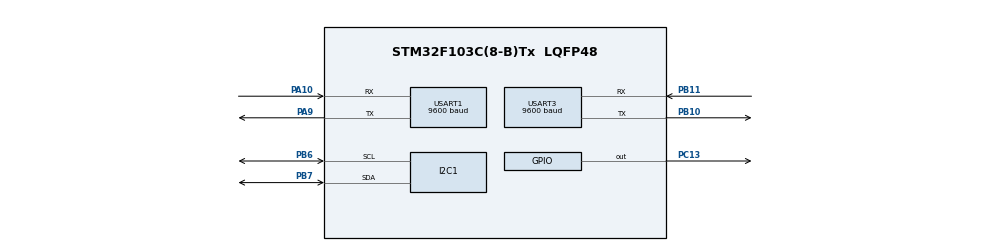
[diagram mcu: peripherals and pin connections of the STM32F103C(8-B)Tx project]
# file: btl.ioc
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Mcu.Family=STM32F1
Mcu.Name=STM32F103C(8-B)Tx
Mcu.Package=LQFP48
NVIC.PriorityGroup=NVIC_PRIORITYGROUP_4
PA10.Mode=Asynchronous
PA10.Signal=USART1_RX
PA13.Mode=Serial_Wire
PA13.Signal=SYS_JTMS-SWDIO
PA14.Mode=Serial_Wire
PA14.Signal=SYS_JTCK-SWCLK
PA9.Mode=Asynchronous
PA9.Signal=USART1_TX
PB10.Mode=Asynchronous
PB10.Signal=USART3_TX
PB11.Mode=Asynchronous
PB11.Signal=USART3_RX
PB6.Mode=I2C
PB6.Signal=I2C1_SCL
PB7.Mode=I2C
PB7.Signal=I2C1_SDA
PC13-TAMPER-RTC.Signal=GPIO_Output
ProjectManager.HeapSize=0x200
ProjectManager.StackSize=0x400
ProjectManager.TargetToolchain=MDK-ARM V5.32
RCC.APB1Freq_Value=8000000
RCC.APB2Freq_Value=8000000
USART1.BaudRate=9600
USART1.VirtualMode=VM_ASYNC
USART3.BaudRate=9600
USART3.VirtualMode=VM_ASYNC
board=custom

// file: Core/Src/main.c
/* USER CODE BEGIN Header */
/**
  ******************************************************************************
  * @file           : main.c
  * @brief          : Main program body
  ******************************************************************************
  * @attention
  *
  * Copyright (c) 2022 STMicroelectronics.
  * All rights reserved.
  *
  * This software is licensed under terms that can be found in the LICENSE file
  * in the root directory of this software component.
  * If no LICENSE file comes with this software, it is provided AS-IS.
  *
  ******************************************************************************
  */
/* USER CODE END Header */
#include "main.h"
#include "string.h"

/* USER CODE BEGIN PTD */
#define SLAVE_ADDRESS_LCD 0x4E
/* USER CODE END PTD */

I2C_HandleTypeDef hi2c1;

UART_HandleTypeDef huart1;
UART_HandleTypeDef huart3;

uint8_t data[20];
uint8_t length;
uint8_t read_buffer;

void SystemClock_Config(void);
static void MX_GPIO_Init(void);
static void MX_I2C1_Init(void);
static void MX_USART1_UART_Init(void);
static void MX_USART3_UART_Init(void);

void lcd_init (void);

void lcd_send_cmd (char cmd);

void lcd_send_data (char data);

void lcd_send_string (char *str, int length);

void lcd_put_cur(int row, int col);

void lcd_clear (void);

int main(void)
{
  /* USER CODE BEGIN 1 */
	int i;
  /* USER CODE END 1 */

  /* MCU Configuration--------------------------------------------------------*/

  /* Reset of all peripherals, Initializes the Flash interface and the Systick. */
  HAL_Init();

  /* Configure the system clock */
  SystemClock_Config();

  /* Initialize all configured peripherals */
  MX_GPIO_Init();
  MX_I2C1_Init();
  MX_USART1_UART_Init();
  MX_USART3_UART_Init();
  /* USER CODE BEGIN 2 */
	lcd_init();
  /* Infinite loop */
  while (1)
  {
		HAL_StatusTypeDef status = HAL_UART_Receive(&huart1, &read_buffer, 1, 1000);
		if (status == HAL_TIMEOUT) {
			continue;
		}

		HAL_UART_Transmit(&huart1, &read_buffer, 1, 1000);

		data[length] = read_buffer;
		if (read_buffer == 13) {
			HAL_GPIO_TogglePin(GPIOC, GPIO_PIN_13);
			HAL_UART_Transmit(&huart3, data, length, 1000);
			HAL_UART_Transmit(&huart3, (uint8_t *)"\r\n", 2, 1000);
			HAL_UART_Transmit(&huart1, (uint8_t *)"\r\n", 2, 1000);

			lcd_clear();
			lcd_put_cur(0, 0);
			lcd_send_string((char *)data, length);

			length = 0;
		} else {
			length++;
		}

		HAL_GPIO_TogglePin(GPIOC, GPIO_PIN_13);
  }
}

void SystemClock_Config(void)
{
  RCC_OscInitTypeDef RCC_OscInitStruct = {0};
  RCC_ClkInitTypeDef RCC_ClkInitStruct = {0};

  /** Initializes the RCC Oscillators according to the specified parameters
  * in the RCC_OscInitTypeDef structure.
  */
  RCC_OscInitStruct.OscillatorType = RCC_OSCILLATORTYPE_HSI;
  RCC_OscInitStruct.HSIState = RCC_HSI_ON;
  RCC_OscInitStruct.HSICalibrationValue = RCC_HSICALIBRATION_DEFAULT;
  RCC_OscInitStruct.PLL.PLLState = RCC_PLL_NONE;
  if (HAL_RCC_OscConfig(&RCC_OscInitStruct) != HAL_OK)
  {
    Error_Handler();
  }

  /** Initializes the CPU, AHB and APB buses clocks
  */
  RCC_ClkInitStruct.ClockType = RCC_CLOCKTYPE_HCLK|RCC_CLOCKTYPE_SYSCLK
                              |RCC_CLOCKTYPE_PCLK1|RCC_CLOCKTYPE_PCLK2;
  RCC_ClkInitStruct.SYSCLKSource = RCC_SYSCLKSOURCE_HSI;
  RCC_ClkInitStruct.AHBCLKDivider = RCC_SYSCLK_DIV1;
  RCC_ClkInitStruct.APB1CLKDivider = RCC_HCLK_DIV1;
  RCC_ClkInitStruct.APB2CLKDivider = RCC_HCLK_DIV1;

  if (HAL_RCC_ClockConfig(&RCC_ClkInitStruct, FLASH_LATENCY_0) != HAL_OK)
  {
    Error_Handler();
  }
}

static void MX_I2C1_Init(void)
{

  hi2c1.Instance = I2C1;
  hi2c1.Init.ClockSpeed = 100000;
  hi2c1.Init.DutyCycle = I2C_DUTYCYCLE_2;
  hi2c1.Init.OwnAddress1 = 0;
  hi2c1.Init.AddressingMode = I2C_ADDRESSINGMODE_7BIT;
  hi2c1.Init.DualAddressMode = I2C_DUALADDRESS_DISABLE;
  hi2c1.Init.OwnAddress2 = 0;
  hi2c1.Init.GeneralCallMode = I2C_GENERALCALL_DISABLE;
  hi2c1.Init.NoStretchMode = I2C_NOSTRETCH_DISABLE;
  if (HAL_I2C_Init(&hi2c1) != HAL_OK)
  {
    Error_Handler();
  }

}

static void MX_USART1_UART_Init(void)
{

  huart1.Instance = USART1;
  huart1.Init.BaudRate = 9600;
  huart1.Init.WordLength = UART_WORDLENGTH_8B;
  huart1.Init.StopBits = UART_STOPBITS_1;
  huart1.Init.Parity = UART_PARITY_NONE;
  huart1.Init.Mode = UART_MODE_TX_RX;
  huart1.Init.HwFlowCtl = UART_HWCONTROL_NONE;
  huart1.Init.OverSampling = UART_OVERSAMPLING_16;
  if (HAL_UART_Init(&huart1) != HAL_OK)
  {
    Error_Handler();
  }

}

static void MX_USART3_UART_Init(void)
{

  huart3.Instance = USART3;
  huart3.Init.BaudRate = 9600;
  huart3.Init.WordLength = UART_WORDLENGTH_8B;
  huart3.Init.StopBits = UART_STOPBITS_1;
  huart3.Init.Parity = UART_PARITY_NONE;
  huart3.Init.Mode = UART_MODE_TX_RX;
  huart3.Init.HwFlowCtl = UART_HWCONTROL_NONE;
  huart3.Init.OverSampling = UART_OVERSAMPLING_16;
  if (HAL_UART_Init(&huart3) != HAL_OK)
  {
    Error_Handler();
  }

}

static void MX_GPIO_Init(void)
{
  GPIO_InitTypeDef GPIO_InitStruct = {0};

  /* GPIO Ports Clock Enable */
  __HAL_RCC_GPIOC_CLK_ENABLE();
  __HAL_RCC_GPIOA_CLK_ENABLE();
  __HAL_RCC_GPIOB_CLK_ENABLE();

  /*Configure GPIO pin Output Level */
  HAL_GPIO_WritePin(GPIOC, GPIO_PIN_13, GPIO_PIN_RESET);

  /*Configure GPIO pin Output Level */
  HAL_GPIO_WritePin(GPIOA, GPIO_PIN_1|GPIO_PIN_2, GPIO_PIN_RESET);

  /*Configure GPIO pin : PC13 */
  GPIO_InitStruct.Pin = GPIO_PIN_13;
  GPIO_InitStruct.Mode = GPIO_MODE_OUTPUT_PP;
  GPIO_InitStruct.Pull = GPIO_NOPULL;
  GPIO_InitStruct.Speed = GPIO_SPEED_FREQ_LOW;
  HAL_GPIO_Init(GPIOC, &GPIO_InitStruct);

  /*Configure GPIO pin : PA1 */
  GPIO_InitStruct.Pin = GPIO_PIN_1;
  GPIO_InitStruct.Mode = GPIO_MODE_OUTPUT_PP;
  GPIO_InitStruct.Pull = GPIO_NOPULL;
  GPIO_InitStruct.Speed = GPIO_SPEED_FREQ_LOW;
  HAL_GPIO_Init(GPIOA, &GPIO_InitStruct);

  /*Configure GPIO pin : PA2 */
  GPIO_InitStruct.Pin = GPIO_PIN_2;
  GPIO_InitStruct.Mode = GPIO_MODE_OUTPUT_PP;
  GPIO_InitStruct.Pull = GPIO_PULLUP;
  GPIO_InitStruct.Speed = GPIO_SPEED_FREQ_LOW;
  HAL_GPIO_Init(GPIOA, &GPIO_InitStruct);

}

/* USER CODE BEGIN 4 */
void lcd_send_cmd (char cmd)
{
  char data_u, data_l;
	uint8_t data_t[4];
	data_u = (cmd&0xf0);
	data_l = ((cmd<<4)&0xf0);
	data_t[0] = data_u|0x0C;  //en=1, rs=0
	data_t[1] = data_u|0x08;  //en=0, rs=0
	data_t[2] = data_l|0x0C;  //en=1, rs=0
	data_t[3] = data_l|0x08;  //en=0, rs=0
	HAL_I2C_Master_Transmit (&hi2c1, SLAVE_ADDRESS_LCD,(uint8_t *) data_t, 4, 100);
}

void lcd_send_data (char data)
{
	char data_u, data_l;
	uint8_t data_t[4];
	data_u = (data&0xf0);
	data_l = ((data<<4)&0xf0);
	data_t[0] = data_u|0x0D;  //en=1, rs=0
	data_t[1] = data_u|0x09;  //en=0, rs=0
	data_t[2] = data_l|0x0D;  //en=1, rs=0
	data_t[3] = data_l|0x09;  //en=0, rs=0
	HAL_I2C_Master_Transmit (&hi2c1, SLAVE_ADDRESS_LCD,(uint8_t *) data_t, 4, 100);
}

void lcd_clear (void)
{
	lcd_send_cmd (0x80);
	for (int i=0; i<70; i++)
	{
		lcd_send_data (' ');
	}
}

void lcd_put_cur(int row, int col)
{
    switch (row)
    {
        case 0:
            col |= 0x80;
            break;
        case 1:
            col |= 0xC0;
            break;
    }

    lcd_send_cmd (col);
}

void lcd_init (void)
{
	// 4 bit initialisation
	HAL_Delay(50);  // wait for >40ms
	lcd_send_cmd (0x30);
	HAL_Delay(5);  // wait for >4.1ms
	lcd_send_cmd (0x30);
	HAL_Delay(1);  // wait for >100us
	lcd_send_cmd (0x30);
	HAL_Delay(10);
	lcd_send_cmd (0x20);  // 4bit mode
	HAL_Delay(10);

  // dislay initialisation
	lcd_send_cmd (0x28); // Function set --> DL=0 (4 bit mode), N = 1 (2 line display) F = 0 (5x8 characters)
	HAL_Delay(1);
	lcd_send_cmd (0x08); //Display on/off control --> D=0,C=0, B=0  ---> display off
	HAL_Delay(1);
	lcd_send_cmd (0x01);  // clear display
	HAL_Delay(1);
	HAL_Delay(1);
	lcd_send_cmd (0x06); //Entry mode set --> I/D = 1 (increment cursor) & S = 0 (no shift)
	HAL_Delay(1);
	lcd_send_cmd (0x0C); //Display on/off control --> D = 1, C and B = 0. (Cursor and blink, last two bits)
}

void lcd_send_string (char *str, int length)
{
	int i;
	for (i = 0; i < length; i++){
		if (i == 16) lcd_put_cur(1, 0);
		lcd_send_data(str[i]);
	}
}
/* USER CODE END 4 */

void Error_Handler(void)
{
  __disable_irq();
  while (1)
  {
  }
}
